MANUFACTURINGGRID 0.005;

LAYER Pwell
    TYPE MASTERSLICE ;
    PROPERTY LEF58_TYPE "TYPE PWELL ;" ;
END Pwell

LAYER Nwell
    TYPE MASTERSLICE ;
    PROPERTY LEF58_TYPE "TYPE NWELL ;" ;
END Nwell

LAYER Poly
    TYPE MASTERSLICE ;
END Poly

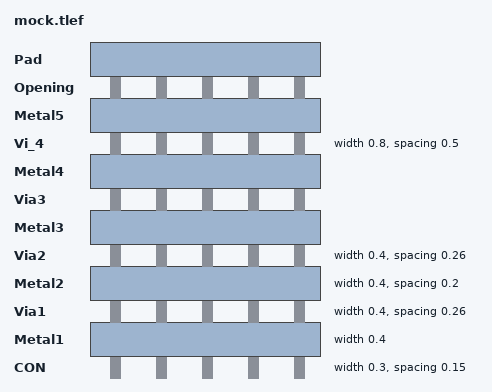
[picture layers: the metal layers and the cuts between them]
LAYER CON
    TYPE CUT;
    SPACING 0.15;
    WIDTH 0.3;
END CON

LAYER Metal1
    TYPE ROUTING;
    WIDTH 0.4;
END Metal1

LAYER Via1
    TYPE CUT;
    SPACING 0.26;
    WIDTH 0.4;
    ENCLOSURE BELOW 0.2;
    ENCLOSURE ABOVE 0.2;
END Via1

LAYER Metal2
    TYPE ROUTING;
    WIDTH 0.4;
    SPACING 0.2;
END Metal2

LAYER Via2
    TYPE CUT;
    SPACING 0.26;
    WIDTH 0.4;
    ENCLOSURE BELOW 0.2;
    ENCLOSURE ABOVE 0.2;
END Via2

LAYER Metal3
    TYPE ROUTING;
END Metal3

LAYER Via3
    TYPE CUT;
END Via3

LAYER Metal4
    TYPE ROUTING ;
END Metal4

LAYER Vi_4
    TYPE CUT ;
    SPACING 0.5;
    WIDTH 0.8;
    ENCLOSURE BELOW 0.2;
    ENCLOSURE ABOVE 0.2;
END Vi_4

LAYER Metal5
    TYPE ROUTING ;
END Metal5

LAYER Opening
    TYPE CUT ;
END Opening

LAYER Pad
    TYPE ROUTING ;
END Pad
